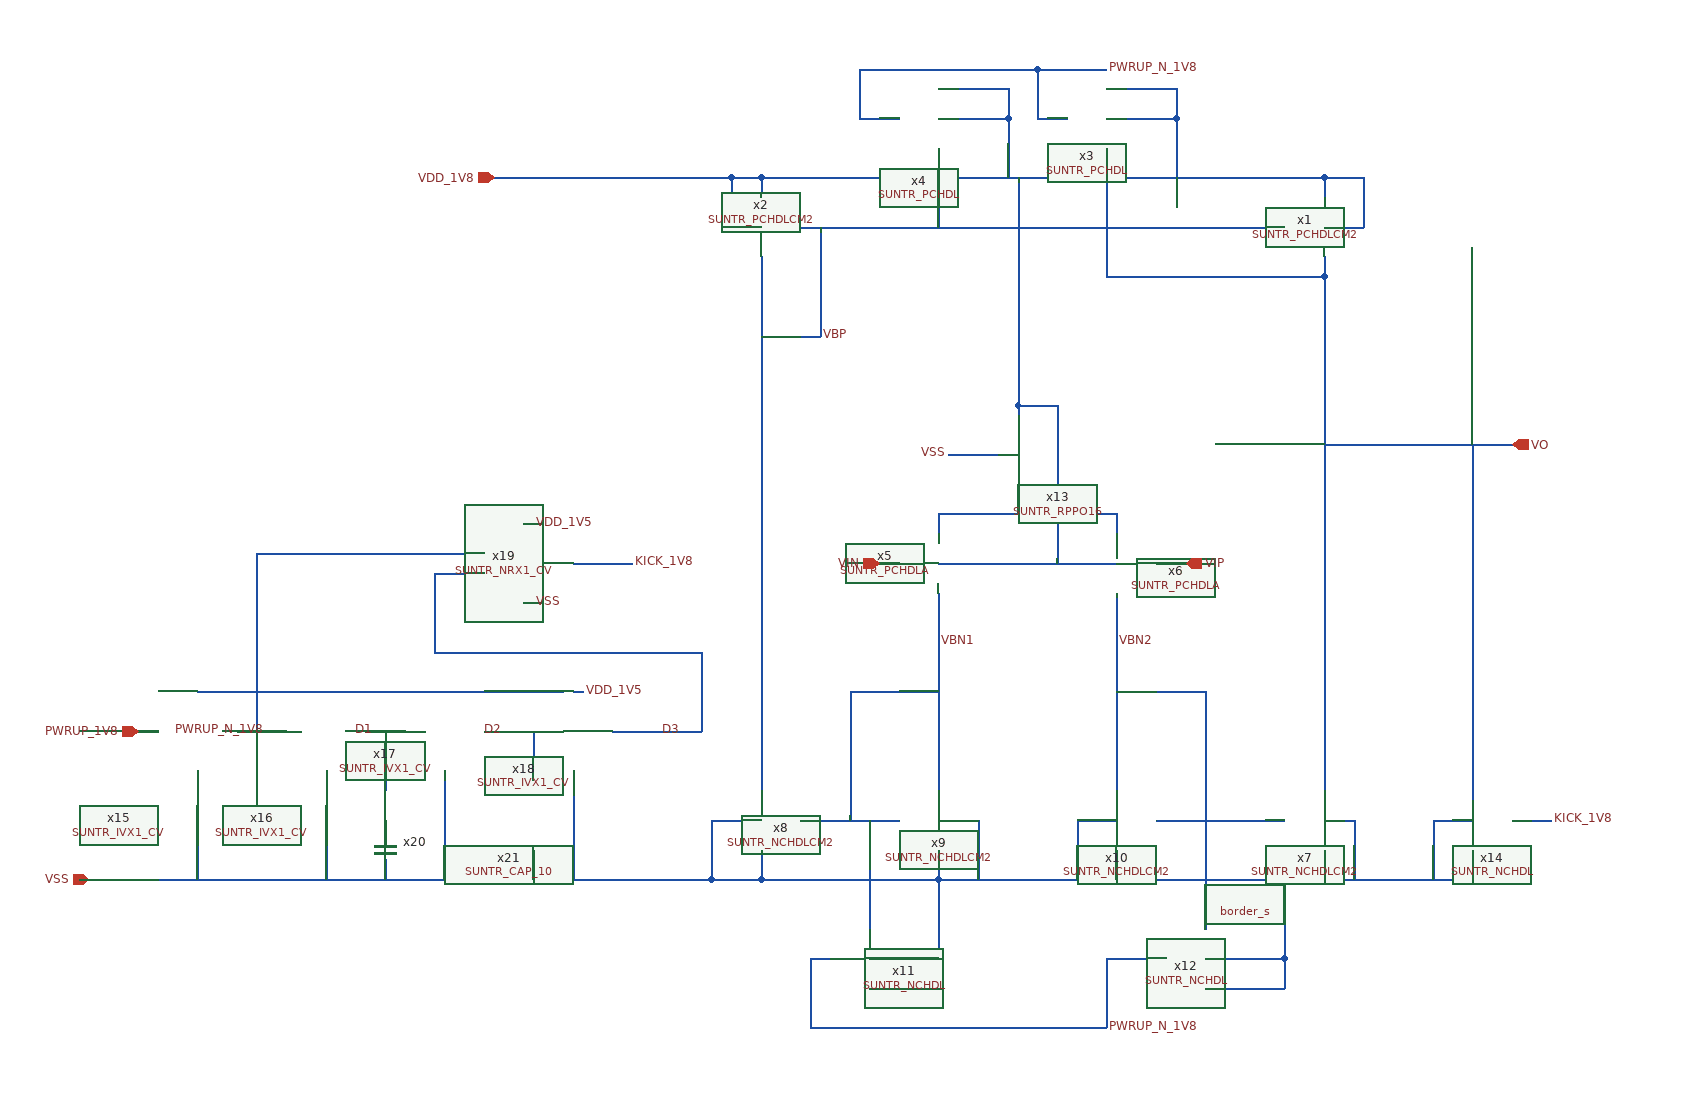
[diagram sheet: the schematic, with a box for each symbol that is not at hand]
v {xschem version=3.0.0 file_version=1.2 }
G {}
K {}
V {}
S {}
E {}
N 90 -810 90 -610 {
lab=VBN1}
N 270 -810 270 -610 {
lab=VBN2}
N 90 -550 90 -520 {
lab=VSS}
N 90 -520 480 -520 {
lab=VSS}
N 480 -550 480 -520 {
lab=VSS}
N 310 -580 440 -580 {
lab=VBN2}
N 270 -550 270 -520 {
lab=VSS}
N -90 -550 -90 -520 {
lab=VSS}
N -90 -520 90 -520 {
lab=VSS}
N -140 -580 -90 -580 {
lab=VSS}
N -140 -580 -140 -520 {
lab=VSS}
N -140 -520 -90 -520 {
lab=VSS}
N -50 -580 50 -580 {
lab=VBN1}
N 0 -710 90 -710 {
lab=VBN1}
N 0 -710 -0 -580 {
lab=VBN1}
N 270 -710 360 -710 {
lab=VBN2}
N 360 -710 360 -580 {
lab=VBN2}
N 360 -580 360 -470 {
lab=VBN2}
N 360 -440 440 -440 {
lab=VSS}
N 440 -520 440 -440 {
lab=VSS}
N 360 -410 440 -410 {
lab=VSS}
N 440 -440 440 -410 {
lab=VSS}
N 20 -410 90 -410 {
lab=VSS}
N 90 -520 90 -410 {
lab=VSS}
N 20 -440 90 -440 {
lab=VSS}
N 20 -580 20 -470 {
lab=VBN1}
N 260 -440 320 -440 {
lab=PWRUP_N_1V8}
N 260 -440 260 -370 {
lab=PWRUP_N_1V8}
N -40 -370 260 -370 {
lab=PWRUP_N_1V8}
N -40 -440 -40 -370 {
lab=PWRUP_N_1V8}
N -40 -440 -20 -440 {
lab=PWRUP_N_1V8}
N 90 -890 90 -870 {
lab=#net1}
N 90 -890 270 -890 {
lab=#net1}
N 270 -890 270 -870 {
lab=#net1}
N 90 -840 270 -840 {
lab=VDD_1V8}
N -90 -1150 -90 -610 {
lab=VBP}
N -50 -1180 440 -1180 {
lab=VBP}
N -90 -1230 -90 -1210 {
lab=VDD_1V8}
N -90 -1230 480 -1230 {
lab=VDD_1V8}
N 480 -1230 480 -1210 {
lab=VDD_1V8}
N 480 -1180 520 -1180 {
lab=VDD_1V8}
N 520 -1230 520 -1180 {
lab=VDD_1V8}
N 480 -1230 520 -1230 {
lab=VDD_1V8}
N -120 -1180 -90 -1180 {
lab=VDD_1V8}
N -120 -1230 -120 -1180 {
lab=VDD_1V8}
N -120 -1230 -90 -1230 {
lab=VDD_1V8}
N 90 -1260 90 -1180 {
lab=VBP}
N 260 -1260 260 -1130 {
lab=VO}
N 260 -1130 480 -1130 {
lab=VO}
N 480 -1150 480 -1130 {
lab=VO}
N 260 -1290 330 -1290 {
lab=VDD_1V8}
N 330 -1290 330 -1230 {
lab=VDD_1V8}
N 260 -1320 330 -1320 {
lab=VDD_1V8}
N 330 -1320 330 -1290 {
lab=VDD_1V8}
N 90 -1290 160 -1290 {
lab=VDD_1V8}
N 160 -1290 160 -1230 {
lab=VDD_1V8}
N 90 -1320 160 -1320 {
lab=VDD_1V8}
N 160 -1320 160 -1290 {
lab=VDD_1V8}
N 480 -1130 480 -610 {
lab=VO}
N 190 -1290 220 -1290 {
lab=PWRUP_N_1V8}
N 190 -1340 190 -1290 {
lab=PWRUP_N_1V8}
N 10 -1290 50 -1290 {
lab=PWRUP_N_1V8}
N 10 -1340 10 -1290 {
lab=PWRUP_N_1V8}
N -360 -1230 -120 -1230 {
lab=VDD_1V8}
N 170 -910 170 -890 {
lab=#net1}
N 210 -1000 210 -840 {
lab=VDD_1V8}
N 170 -1000 210 -1000 {
lab=VDD_1V8}
N 170 -1000 170 -990 {
lab=VDD_1V8}
N 170 -1230 170 -1000 {
lab=VDD_1V8}
N 100 -950 150 -950 {
lab=VSS}
N -90 -1070 -30 -1070 {
lab=VBP}
N -30 -1180 -30 -1070 {
lab=VBP}
N 480 -960 670 -960 {
lab=VO}
N 630 -550 630 -520 {
lab=VSS}
N 480 -520 630 -520 {
lab=VSS}
N 590 -580 630 -580 {
lab=VSS}
N 590 -580 590 -520 {
lab=VSS}
N 480 -580 510 -580 {
lab=VSS}
N 510 -580 510 -520 {
lab=VSS}
N 230 -580 270 -580 {
lab=VSS}
N 230 -580 230 -520 {
lab=VSS}
N 90 -580 130 -580 {
lab=VSS}
N 130 -580 130 -520 {
lab=VSS}
N 630 -960 630 -600 {
lab=VO}
N 670 -580 710 -580 {
lab=KICK_1V8}
N 10 -1340 190 -1340 {
lab=PWRUP_N_1V8}
N 190 -1340 260 -1340 {
lab=PWRUP_N_1V8}
N -780 -520 -140 -520 {
lab=VSS}
N -330 -880 -320 -880 {
lab=VDD_1V5}
N -330 -800 -320 -800 {
lab=VSS}
N -370 -670 -320 -670 {
lab=D2}
N -490 -670 -450 -670 {
lab=D1}
N -620 -670 -570 -670 {
lab=PWRUP_N_1V8}
N -280 -710 -270 -710 {
lab=VDD_1V5}
N -410 -710 -290 -710 {
lab=#net2}
N -530 -710 -410 -710 {
lab=#net2}
N -660 -710 -530 -710 {
lab=#net2}
N -320 -670 -320 -620 {
lab=D2}
N -470 -670 -470 -610 {
lab=D1}
N -470 -540 -470 -520 {
lab=VSS}
N -320 -550 -320 -520 {
lab=VSS}
N -410 -630 -410 -520 {
lab=VSS}
N -280 -630 -280 -520 {
lab=VSS}
N -530 -630 -530 -520 {
lab=VSS}
N -660 -630 -660 -520 {
lab=VSS}
N -730 -670 -700 -670 {
lab=PWRUP_1V8}
N -600 -820 -600 -670 {
lab=PWRUP_N_1V8}
N -600 -850 -600 -820 {
lab=PWRUP_N_1V8}
N -600 -850 -370 -850 {
lab=PWRUP_N_1V8}
N -240 -670 -150 -670 {
lab=D3}
N -150 -750 -150 -670 {
lab=D3}
N -420 -750 -150 -750 {
lab=D3}
N -420 -830 -420 -750 {
lab=D3}
N -420 -830 -370 -830 {
lab=D3}
N -280 -840 -220 -840 {
lab=KICK_1V8}
N 310 -840 350 -840 {
lab=VIP}
N 20 -840 50 -840 {
lab=VIN}
C {cborder/border_s.sym} 400 -480 0 0 {}
C {SUN_TR_SKY130NM/SUNTR_PCHDLCM2.sym} 440 -1180 0 0 {name=x1 xoffset=0 yoffset=0 angle=0 M=1}
C {SUN_TR_SKY130NM/SUNTR_PCHDLCM2.sym} -50 -1180 0 1 {name=x2 xoffset=0 yoffset=0 angle=0 M=1}
C {SUN_TR_SKY130NM/SUNTR_PCHDL.sym} 220 -1290 0 0 {name=x3 xoffset=0 yoffset=0 angle=0 M=1}
C {SUN_TR_SKY130NM/SUNTR_PCHDL.sym} 50 -1290 0 0 {name=x4 xoffset=0 yoffset=0 angle=0 M=1}
C {SUN_TR_SKY130NM/SUNTR_NCHDLCM2.sym} 440 -580 0 0 {name=x7 xoffset=0 yoffset=0 angle=0 M=1}
C {SUN_TR_SKY130NM/SUNTR_NCHDLCM2.sym} -50 -580 0 1 {name=x8 xoffset=0 yoffset=0 angle=0 M=1}
C {SUN_TR_SKY130NM/SUNTR_NCHDLCM2.sym} 50 -580 0 0 {name=x9 xoffset=0 yoffset=0 angle=0 M=1}
C {SUN_TR_SKY130NM/SUNTR_NCHDLCM2.sym} 310 -580 0 1 {name=x10 xoffset=0 yoffset=0 angle=0 M=1}
C {SUN_TR_SKY130NM/SUNTR_NCHDL.sym} -20 -440 0 0 {name=x11 xoffset=0 yoffset=0 angle=0 M=1}
C {SUN_TR_SKY130NM/SUNTR_NCHDL.sym} 320 -440 0 0 {name=x12 xoffset=0 yoffset=0 angle=0 M=1}
C {SUN_TR_SKY130NM/SUNTR_PCHDLA.sym} 50 -840 0 0 {name=x5 xoffset=0 yoffset=0 angle=0 M=1}
C {SUN_TR_SKY130NM/SUNTR_PCHDLA.sym} 310 -840 0 1 {name=x6 xoffset=0 yoffset=0 angle=0 M=1}
C {devices/ipin.sym} -360 -1230 0 0 {name=p1 lab=VDD_1V8}
C {SUN_TR_SKY130NM/SUNTR_RPPO16.sym} 170 -990 1 0 {name=x13 xoffset=0 yoffset=0 angle=0 M=1}
C {devices/lab_pin.sym} 100 -950 0 0 {name=l1 sig_type=std_logic lab=VSS}
C {devices/lab_pin.sym} -30 -1070 0 1 {name=l2 sig_type=std_logic lab=VBP}
C {devices/opin.sym} 670 -960 0 0 {name=p2 lab=VO}
C {SUN_TR_SKY130NM/SUNTR_NCHDL.sym} 670 -580 0 1 {name=x14 xoffset=0 yoffset=0 angle=0 M=1}
C {devices/lab_pin.sym} 710 -580 0 1 {name=l3 sig_type=std_logic lab=KICK_1V8}
C {devices/lab_pin.sym} 260 -370 0 1 {name=l4 sig_type=std_logic lab=PWRUP_N_1V8}
C {devices/lab_pin.sym} 260 -1340 0 1 {name=l5 sig_type=std_logic lab=PWRUP_N_1V8}
C {devices/lab_pin.sym} 90 -760 0 1 {name=l6 sig_type=std_logic lab=VBN1}
C {devices/lab_pin.sym} 270 -760 0 1 {name=l7 sig_type=std_logic lab=VBN2}
C {devices/ipin.sym} -770 -520 0 0 {name=p3 lab=VSS}
C {SUN_TR_SKY130NM/SUNTR_IVX1_CV.sym} -700 -670 0 0 {name=x15 xoffset=0 yoffset=0 angle=0 M=1}
C {SUN_TR_SKY130NM/SUNTR_IVX1_CV.sym} -570 -670 0 0 {name=x16 xoffset=0 yoffset=0 angle=0 M=1}
C {SUN_TR_SKY130NM/SUNTR_IVX1_CV.sym} -450 -670 0 0 {name=x17 xoffset=0 yoffset=0 angle=0 M=1}
C {SUN_TR_SKY130NM/SUNTR_IVX1_CV.sym} -320 -670 0 0 {name=x18 xoffset=0 yoffset=0 angle=0 M=1}
C {SUN_TR_SKY130NM/SUNTR_NRX1_CV.sym} -370 -830 0 0 {name=x19 xoffset=0 yoffset=0 angle=0 M=1}
C {devices/lab_pin.sym} -320 -880 0 1 {name=l8 sig_type=std_logic lab=VDD_1V5}
C {devices/lab_pin.sym} -320 -800 0 1 {name=l9 sig_type=std_logic lab=VSS}
C {devices/lab_pin.sym} -270 -710 0 1 {name=l10 sig_type=std_logic lab=VDD_1V5}
C {SUN_TR_SKY130NM/SUNTR_CAP_10.sym} -470 -550 0 0 {name=x20 xoffset=0 yoffset=0 angle=0 M=1}
C {SUN_TR_SKY130NM/SUNTR_CAP_10.sym} -320 -560 0 0 {name=x21 xoffset=0 yoffset=0 angle=0 M=1}
C {devices/ipin.sym} -720 -670 0 0 {name=p4 lab=PWRUP_1V8}
C {devices/lab_pin.sym} -220 -840 0 1 {name=l11 sig_type=std_logic lab=KICK_1V8}
C {devices/lab_pin.sym} -590 -670 1 1 {name=l12 sig_type=std_logic lab=PWRUP_N_1V8}
C {devices/ipin.sym} 30 -840 0 0 {name=p5 lab=VIN}
C {devices/ipin.sym} 340 -840 0 1 {name=p6 lab=VIP}
C {devices/lab_pin.sym} -480 -670 3 1 {name=l13 sig_type=std_logic lab=D1}
C {devices/lab_pin.sym} -350 -670 3 1 {name=l14 sig_type=std_logic lab=D2}
C {devices/lab_pin.sym} -170 -670 3 1 {name=l15 sig_type=std_logic lab=D3}
